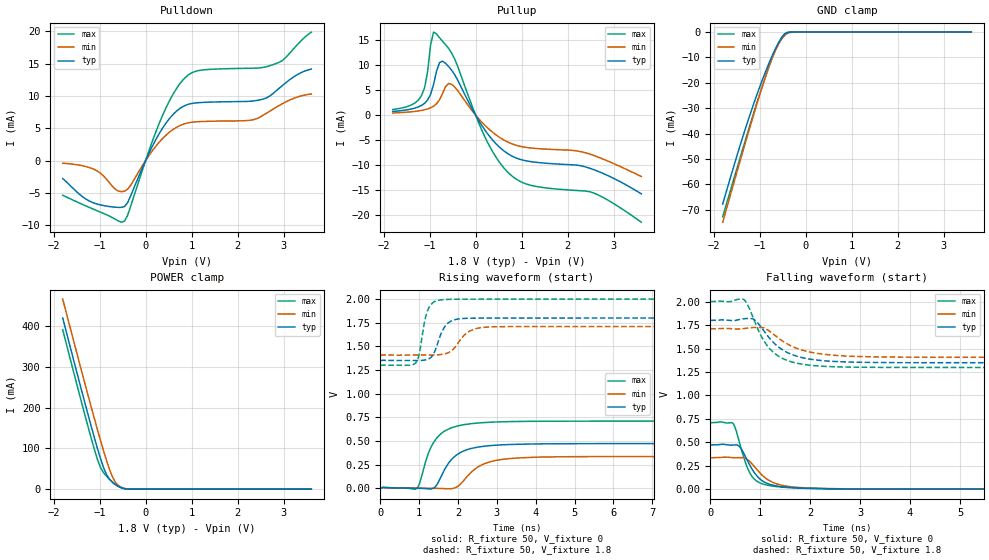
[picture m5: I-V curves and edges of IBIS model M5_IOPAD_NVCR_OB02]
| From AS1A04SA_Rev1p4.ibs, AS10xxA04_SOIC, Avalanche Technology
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[Model] M5_IOPAD_NVCR_OB02
Model_type I/O
Enable   Active-High
Vinl  =  0.54
Vinh  =  1.26
Vmeas =  0.9
Cref  =  30e-12
| Capacitance  typ   min   max
C_comp   3.869840e-12   3.575244e-12   4.229518e-12
| Variables   typ   min   max
[GND Clamp Reference]   0   0   0
[POWER Clamp Reference]   1.8   1.71   2
[Pulldown Reference]   0   0   0
[Pullup Reference]   1.8   1.71   2
[Temperature Range]   25   125   -40
[Voltage Range]   1.8   1.71   2
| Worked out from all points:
|   slope of the pulldown table from 0 to 0.27 V, typ, clamps not added: 70.1 ohm
|   slope of the pullup table from 0 to 0.27 V, typ, clamps not added: 70.5 ohm
|   GND clamp passes 1 mA (typ) near -0.46 V on its own axis
|   POWER clamp passes 1 mA (typ) near -0.44 V on its own axis
|   falling waveform, R_fixture 50, V_fixture 0: 20-80 % time 352ps typ, 436ps min, 280ps max; typ from 0.471 V to 0 V
|   falling waveform, R_fixture 50, V_fixture 1.8: 20-80 % time 579ps typ, 685ps min, 480ps max; typ from 1.8 V to 1.35 V
|   rising waveform, R_fixture 50, V_fixture 0: 20-80 % time 529ps typ, 625ps min, 463ps max; typ from 0 V to 0.471 V
|   rising waveform, R_fixture 50, V_fixture 1.8: 20-80 % time 269ps typ, 383ps min, 192ps max; typ from 1.35 V to 1.8 V
[GND Clamp]
| Voltage   I(typ)   I(min)   I(max)
-1.8V     -67.84mA   -74.98mA   -72.81mA
-1.499V   -49.26mA   -55.7mA    -54.28mA
-1.303V   -37.87mA   -43.36mA   -42.4mA
-1.043V   -23.96mA   -27.4mA    -27.1mA
-847.2mV  -14.58mA   -16.27mA   -16.36mA
-716.9mV  -8.973mA   -9.798mA   -9.837mA
-651.7mV  -6.447mA   -7.048mA   -6.896mA
-521.4mV  -2.255mA   -2.801mA   -2.141mA
-456.2mV  -849.3uA   -1.361mA   -679.4uA
-391mV    -172uA     -473.2uA   -88.88uA
-260.7mV  -2.088uA   -22.04uA   -254.3nA
3.6V      0A         0A         0A
[POWER Clamp]
| Voltage   I(typ)   I(min)   I(max)
-1.8V     419.8mA    466.1mA    390.9mA
-1.303V   205.4mA    252.8mA    175.7mA
-1.043V   98.85mA    144.9mA    72.14mA
-977.6mV  74.56mA    119mA      52.56mA
-912.4mV  52.76mA    93.87mA    40.16mA
-847.2mV  35.48mA    69.92mA    31.71mA
-716.9mV  16.42mA    29.44mA    17.31mA
-651.7mV  10.9mA     16.21mA    11.28mA
-586.6mV  6.514mA    8.5mA      6.386mA
-456.2mV  1.168mA    1.854mA    921.1uA
-325.9mV  31.2uA     159.5uA    13.68uA
3.6V      0A         0A         0A
[Pulldown]
| Voltage   I(typ)   I(min)   I(max)
-1.8V     -2.779mA   -403.4uA   -5.361mA
-1.173V   -6.412mA   -1.187mA   -7.394mA
-651.7mV  -7.214mA   -4.457mA   -9.099mA
-456.2mV  -7.098mA   -4.726mA   -9.361mA
310.3mV   4.353mA    2.972mA    6.008mA
620.7mV   7.316mA    4.933mA    10.57mA
869mV     8.567mA    5.75mA     12.9mA
1.179V    8.982mA    6.038mA    13.97mA
2.283V    9.19mA     6.258mA    14.3mA
2.766V    10.37mA    7.95mA     14.85mA
2.972V    11.63mA    8.812mA    15.49mA
3.6V      14.16mA    10.31mA    19.89mA
[Pullup]
| Voltage   I(typ)   I(min)   I(max)
-1.8V     713.6uA    418.6uA    1.098mA
-1.173V   1.921mA    929uA      3.898mA
-1.043V   2.99mA     1.225mA    8.588mA
-977.6mV  4.11mA     1.452mA    14mA
-912.4mV  6.104mA    1.777mA    16.54mA
-782.1mV  10.46mA    3.06mA     15.4mA
-651.7mV  10.31mA    5.686mA    14.04mA
-456.2mV  8.081mA    5.617mA    11.23mA
248.3mV   -3.569mA   -2.453mA   -5.217mA
744.8mV   -7.943mA   -5.559mA   -11.78mA
2.559V    -10.86mA   -8.024mA   -15.51mA
3.6V      -15.7mA    -12.25mA   -21.35mA
[Ramp]
dV/dt_r   0.282807/0.529465n  0.201049/0.625406n  0.425437/0.462933n
dV/dt_f   0.271206/0.579502n  0.182721/0.684992n  0.421848/0.479962n
R_load = 50
[Falling Waveform]
R_fixture = 50
V_fixture = 0
V_fixture_min = 0
V_fixture_max = 0
| Time   V(typ)   V(min)   V(max)
0s        471.3mV    335.1mV    709.1mV
456.1ps   470mV      334.8mV    699.6mV
507.4ps   472.5mV    335mV      640.9mV
592.1ps   450.1mV    336.1mV    482.5mV
743.8ps   304.7mV    315.6mV    226.6mV
918.2ps   151.1mV    218.6mV    90.72mV
1.152ns   58.72mV    100.6mV    41.21mV
1.537ns   20.7mV     31.46mV    17.55mV
3.312ns   1.001mV    1.561mV    678.5uV
21.88ns   148.3nV    1.007uV    196.1nV
[Falling Waveform]
R_fixture = 50
V_fixture = 1.8
V_fixture_min = 1.71
V_fixture_max = 2
| Time   V(typ)   V(min)   V(max)
0s        1.8V       1.71V      2V
668.7ps   1.817V     1.713V     2.023V
757.8ps   1.82V      1.719V     1.955V
896ps     1.802V     1.725V     1.779V
1.076ns   1.686V     1.719V     1.579V
1.279ns   1.556V     1.646V     1.452V
1.683ns   1.426V     1.512V     1.35V
2.237ns   1.371V     1.441V     1.311V
4.381ns   1.349V     1.406V     1.298V
21.88ns   1.348V     1.405V     1.297V
[Rising Waveform]
R_fixture = 50
V_fixture = 0
V_fixture_min = 0
V_fixture_max = 0
| Time   V(typ)   V(min)   V(max)
0s        64.51nV    875.2nV    117.5nV
929.7ps   137.8uV    994.8uV    -4.858mV
1.021ns   -1.205mV   800.6uV    63.07mV
1.241ns   -8.135mV   -80.01uV   372.4mV
1.458ns   37.82mV    -1.795mV   533.9mV
1.889ns   326.4mV    -47.96uV   645.9mV
2.545ns   436.5mV    231.5mV    690.7mV
3.129ns   458.2mV    304.1mV    702.2mV
4.501ns   469.7mV    331.2mV    708.3mV
21.88ns   471.3mV    335.1mV    709.1mV
[Rising Waveform]
R_fixture = 50
V_fixture = 1.8
V_fixture_min = 1.71
V_fixture_max = 2
| Time   V(typ)   V(min)   V(max)
0s        1.348V     1.405V     1.297V
908.2ps   1.349V     1.407V     1.323V
987.9ps   1.35V      1.407V     1.397V
1.13ns    1.354V     1.407V     1.742V
1.237ns   1.366V     1.407V     1.897V
1.37ns    1.419V     1.407V     1.966V
1.649ns   1.701V     1.42V      1.995V
2.265ns   1.797V     1.652V     1.999V
2.833ns   1.799V     1.705V     1.999V
21.88ns   1.8V       1.71V      2V
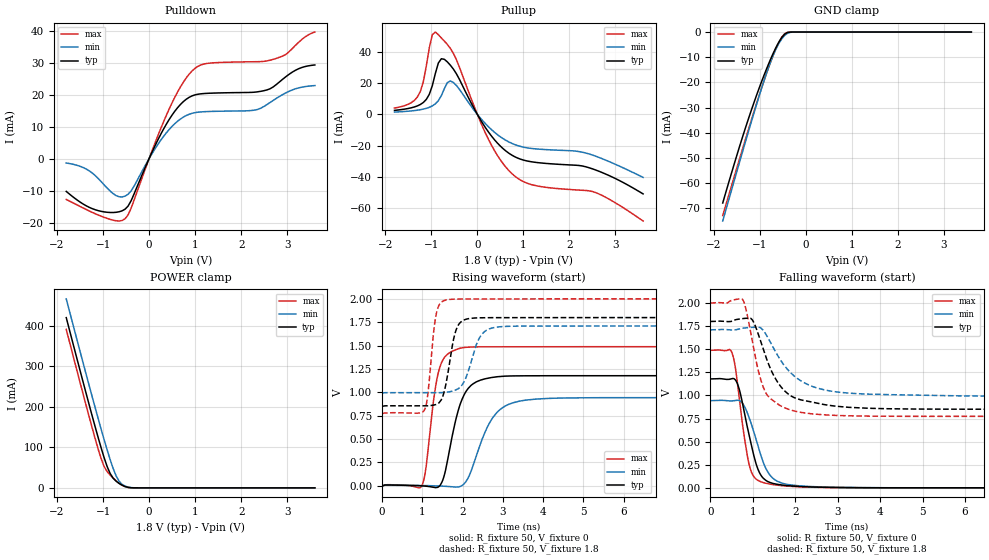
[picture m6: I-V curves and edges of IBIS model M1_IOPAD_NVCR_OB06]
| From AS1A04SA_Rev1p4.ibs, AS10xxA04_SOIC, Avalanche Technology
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[Model] M1_IOPAD_NVCR_OB06
Model_type I/O
Enable   Active-High
Vinl  =  0.54
Vinh  =  1.26
Vmeas =  0.9
Cref  =  30e-12
| Capacitance  typ   min   max
C_comp   3.869840e-12   3.575244e-12   4.229518e-12
| Variables   typ   min   max
[GND Clamp Reference]   0   0   0
[POWER Clamp Reference]   1.8   1.71   2
[Pulldown Reference]   0   0   0
[Pullup Reference]   1.8   1.71   2
[Temperature Range]   25   125   -40
[Voltage Range]   1.8   1.71   2
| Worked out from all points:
|   slope of the pulldown table from 0 to 0.27 V, typ, clamps not added: 33.5 ohm
|   slope of the pullup table from 0 to 0.27 V, typ, clamps not added: 21.7 ohm
|   GND clamp passes 1 mA (typ) near -0.46 V on its own axis
|   POWER clamp passes 1 mA (typ) near -0.44 V on its own axis
|   falling waveform, R_fixture 50, V_fixture 0: 20-80 % time 349ps typ, 414ps min, 269ps max; typ from 1.18 V to 0 V
|   falling waveform, R_fixture 50, V_fixture 1.8: 20-80 % time 603ps typ, 792ps min, 399ps max; typ from 1.8 V to 0.85 V
|   rising waveform, R_fixture 50, V_fixture 0: 20-80 % time 395ps typ, 556ps min, 266ps max; typ from 0 V to 1.18 V
|   rising waveform, R_fixture 50, V_fixture 1.8: 20-80 % time 237ps typ, 337ps min, 166ps max; typ from 0.85 V to 1.8 V
[GND Clamp]
| Voltage   I(typ)   I(min)   I(max)
-1.8V     -67.84mA   -74.98mA   -72.81mA
-1.499V   -49.26mA   -55.7mA    -54.28mA
-1.303V   -37.87mA   -43.36mA   -42.4mA
-1.043V   -23.96mA   -27.4mA    -27.1mA
-847.2mV  -14.58mA   -16.27mA   -16.36mA
-716.9mV  -8.973mA   -9.798mA   -9.837mA
-651.7mV  -6.447mA   -7.048mA   -6.896mA
-521.4mV  -2.255mA   -2.801mA   -2.141mA
-456.2mV  -849.3uA   -1.361mA   -679.4uA
-391mV    -172uA     -473.2uA   -88.88uA
-260.7mV  -2.088uA   -22.04uA   -254.3nA
3.6V      0A         0A         0A
[POWER Clamp]
| Voltage   I(typ)   I(min)   I(max)
-1.8V     419.8mA    466.1mA    390.9mA
-1.303V   205.4mA    252.8mA    175.7mA
-1.043V   98.85mA    144.9mA    72.14mA
-977.6mV  74.56mA    119mA      52.56mA
-912.4mV  52.76mA    93.87mA    40.16mA
-847.2mV  35.48mA    69.92mA    31.71mA
-716.9mV  16.42mA    29.44mA    17.31mA
-651.7mV  10.9mA     16.21mA    11.28mA
-586.6mV  6.514mA    8.5mA      6.386mA
-456.2mV  1.168mA    1.854mA    921.1uA
-325.9mV  31.2uA     159.5uA    13.68uA
3.6V      0A         0A         0A
[Pulldown]
| Voltage   I(typ)   I(min)   I(max)
-1.8V     -10.27mA   -1.377mA   -12.78mA
-1.108V   -16.27mA   -6.192mA   -17.63mA
-716.9mV  -16.8mA    -11.58mA   -19.45mA
-521.4mV  -15.81mA   -11.74mA   -18.8mA
-391mV    -13.18mA   -10.1mA    -15.51mA
372.4mV   10.72mA    8.023mA    13.47mA
931mV     19.6mA     14.15mA    27.38mA
1.241V    20.39mA    14.69mA    29.72mA
2.283V    20.76mA    15.14mA    30.29mA
2.697V    22.43mA    18.2mA     31.03mA
3.179V    27.62mA    21.83mA    35.42mA
3.6V      29.28mA    22.83mA    39.58mA
[Pullup]
| Voltage   I(typ)   I(min)   I(max)
-1.8V     2.579mA    1.494mA    4.066mA
-1.238V   6.367mA    3.011mA    14.71mA
-977.6mV  18.53mA    5.465mA    51.24mA
-912.4mV  26.3mA     6.791mA    52.93mA
-782.1mV  35.76mA    12.04mA    49.13mA
-651.7mV  33.73mA    20.39mA    44.94mA
-521.4mV  29.14mA    20.54mA    39.28mA
186.2mV   -8.975mA   -6.295mA   -12.69mA
744.8mV   -26.1mA    -18.58mA   -37.9mA
1.241V    -30.74mA   -22.09mA   -45.62mA
2.559V    -35.62mA   -26.73mA   -50.14mA
3.6V      -51.1mA    -40.49mA   -68.52mA
[Ramp]
dV/dt_r   0.70702/0.39465n  0.566097/0.556387n  0.892904/0.26596n
dV/dt_f   0.569737/0.602924n  0.430715/0.791806n  0.736237/0.398943n
R_load = 50
[Falling Waveform]
R_fixture = 50
V_fixture = 0
V_fixture_min = 0
V_fixture_max = 0
| Time   V(typ)   V(min)   V(max)
0s        1.178V     943.5mV    1.488V
505.1ps   1.181V     940.6mV    1.468V
580.5ps   1.173V     945.6mV    1.331V
666.6ps   1.092V     947.3mV    1.026V
802.5ps   815.2mV    883.3mV    548.2mV
942.9ps   513.8mV    723.4mV    204.1mV
1.169ns   155.3mV    384.4mV    69.9mV
1.455ns   50.58mV    112.7mV    36.41mV
3.27ns    2.368mV    3.858mV    1.53mV
21.88ns   366.3nV    1.238uV    391.8nV
[Falling Waveform]
R_fixture = 50
V_fixture = 1.8
V_fixture_min = 1.71
V_fixture_max = 2
| Time   V(typ)   V(min)   V(max)
0s        1.8V       1.71V      2V
755.5ps   1.831V     1.727V     2.041V
844.1ps   1.835V     1.732V     1.927V
996.5ps   1.813V     1.737V     1.569V
1.16ns    1.624V     1.737V     1.217V
1.324ns   1.398V     1.652V     1.016V
1.745ns   1.052V     1.324V     867.5mV
2.335ns   934mV      1.11V      803.4mV
5.615ns   851.2mV    996mV      773.6mV
21.88ns   850.4mV    992.1mV    772.9mV
[Rising Waveform]
R_fixture = 50
V_fixture = 0
V_fixture_min = 0
V_fixture_max = 0
| Time   V(typ)   V(min)   V(max)
0s        82.33nV    858.7nV    142.2nV
973ps     173.1uV    2.939mV    -10.32mV
1.088ns   -3.879mV   2.255mV    184mV
1.28ns    -16.31mV   191.4uV    915.4mV
1.431ns   279.3uV    -2.2mV     1.264V
1.99ns    928.5mV    3.83mV     1.477V
2.258ns   1.09V      213.3mV    1.486V
2.757ns   1.161V     733.4mV    1.487V
3.563ns   1.177V     916.5mV    1.488V
21.88ns   1.178V     943.5mV    1.488V
[Rising Waveform]
R_fixture = 50
V_fixture = 1.8
V_fixture_min = 1.71
V_fixture_max = 2
| Time   V(typ)   V(min)   V(max)
0s        850.4mV    992.1mV    772.9mV
1.064ns   854.1mV    995.5mV    819mV
1.134ns   855.2mV    995.3mV    971.4mV
1.336ns   869.6mV    995.1mV    1.817V
1.512ns   961.3mV    997.5mV    1.976V
1.639ns   1.214V     1.004V     1.992V
1.926ns   1.739V     1.051V     1.998V
2.46ns    1.798V     1.61V      1.999V
2.996ns   1.799V     1.704V     1.999V
21.88ns   1.8V       1.71V      2V
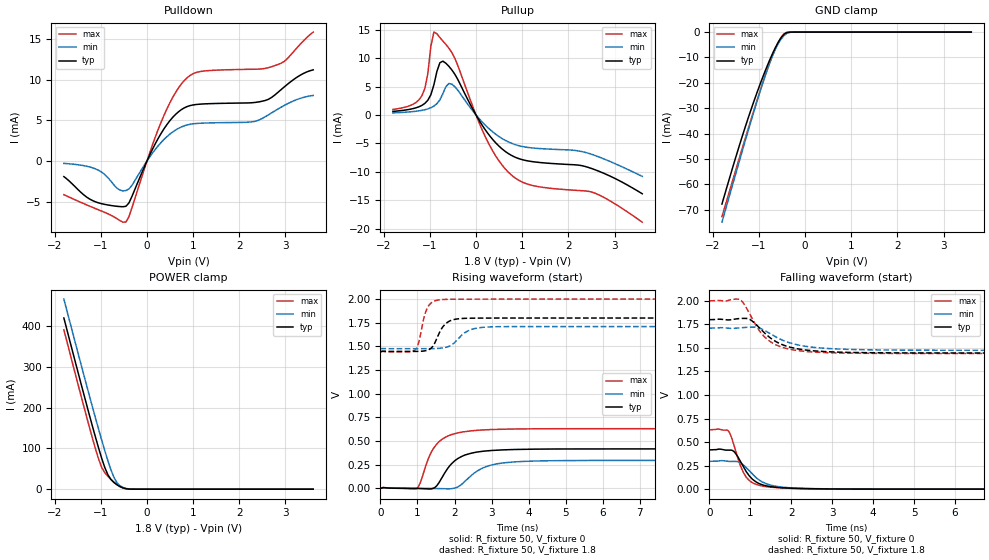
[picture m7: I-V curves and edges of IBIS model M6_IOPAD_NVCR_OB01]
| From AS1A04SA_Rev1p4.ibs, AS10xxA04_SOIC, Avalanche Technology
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[Model] M6_IOPAD_NVCR_OB01
Model_type I/O
Enable   Active-High
Vinl  =  0.54
Vinh  =  1.26
Vmeas =  0.9
Cref  =  30e-12
| Capacitance  typ   min   max
C_comp   3.869840e-12   3.575244e-12   4.229518e-12
| Variables   typ   min   max
[GND Clamp Reference]   0   0   0
[POWER Clamp Reference]   1.8   1.71   2
[Pulldown Reference]   0   0   0
[Pullup Reference]   1.8   1.71   2
[Temperature Range]   25   125   -40
[Voltage Range]   1.8   1.71   2
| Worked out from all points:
|   slope of the pulldown table from 0 to 0.27 V, typ, clamps not added: 88.4 ohm
|   slope of the pullup table from 0 to 0.27 V, typ, clamps not added: 80.1 ohm
|   GND clamp passes 1 mA (typ) near -0.46 V on its own axis
|   POWER clamp passes 1 mA (typ) near -0.44 V on its own axis
|   falling waveform, R_fixture 50, V_fixture 0: 20-80 % time 409ps typ, 500ps min, 329ps max; typ from 0.417 V to 0 V
|   falling waveform, R_fixture 50, V_fixture 1.8: 20-80 % time 714ps typ, 848ps min, 588ps max; typ from 1.8 V to 1.45 V
|   rising waveform, R_fixture 50, V_fixture 0: 20-80 % time 559ps typ, 669ps min, 484ps max; typ from 0 V to 0.417 V
|   rising waveform, R_fixture 50, V_fixture 1.8: 20-80 % time 291ps typ, 416ps min, 205ps max; typ from 1.45 V to 1.8 V
[GND Clamp]
| Voltage   I(typ)   I(min)   I(max)
-1.8V     -67.84mA   -74.98mA   -72.81mA
-1.499V   -49.26mA   -55.7mA    -54.28mA
-1.303V   -37.87mA   -43.36mA   -42.4mA
-1.043V   -23.96mA   -27.4mA    -27.1mA
-847.2mV  -14.58mA   -16.27mA   -16.36mA
-716.9mV  -8.973mA   -9.798mA   -9.837mA
-651.7mV  -6.447mA   -7.048mA   -6.896mA
-521.4mV  -2.255mA   -2.801mA   -2.141mA
-456.2mV  -849.3uA   -1.361mA   -679.4uA
-391mV    -172uA     -473.2uA   -88.88uA
-260.7mV  -2.088uA   -22.04uA   -254.3nA
3.6V      0A         0A         0A
[POWER Clamp]
| Voltage   I(typ)   I(min)   I(max)
-1.8V     419.8mA    466.1mA    390.9mA
-1.303V   205.4mA    252.8mA    175.7mA
-1.043V   98.85mA    144.9mA    72.14mA
-977.6mV  74.56mA    119mA      52.56mA
-912.4mV  52.76mA    93.87mA    40.16mA
-847.2mV  35.48mA    69.92mA    31.71mA
-716.9mV  16.42mA    29.44mA    17.31mA
-651.7mV  10.9mA     16.21mA    11.28mA
-586.6mV  6.514mA    8.5mA      6.386mA
-456.2mV  1.168mA    1.854mA    921.1uA
-325.9mV  31.2uA     159.5uA    13.68uA
3.6V      0A         0A         0A
[Pulldown]
| Voltage   I(typ)   I(min)   I(max)
-1.8V     -1.924mA   -299.7uA   -4.159mA
-1.173V   -4.896mA   -848.4uA   -5.734mA
-912.4mV  -5.354mA   -1.678mA   -6.345mA
-651.7mV  -5.587mA   -3.335mA   -7.105mA
-456.2mV  -5.586mA   -3.649mA   -7.526mA
310.3mV   3.446mA    2.313mA    4.855mA
558.6mV   5.391mA    3.587mA    7.858mA
806.9mV   6.547mA    4.337mA    9.919mA
1.179V    7.023mA    4.664mA    11.06mA
2.283V    7.188mA    4.836mA    11.32mA
2.834V    8.456mA    6.4mA      11.9mA
3.6V      11.24mA    8.086mA    15.9mA
[Pullup]
| Voltage   I(typ)   I(min)   I(max)
-1.8V     628.3uA    368.4uA    967.2uA
-1.173V   1.677mA    813.9uA    3.367mA
-1.043V   2.6mA      1.072mA    7.324mA
-977.6mV  3.564mA    1.27mA     12.11mA
-912.4mV  5.287mA    1.553mA    14.55mA
-782.1mV  9.175mA    2.668mA    13.58mA
-651.7mV  9.08mA     4.977mA    12.38mA
-456.2mV  7.117mA    4.941mA    9.904mA
248.3mV   -3.143mA   -2.157mA   -4.604mA
744.8mV   -6.991mA   -4.887mA   -10.39mA
2.559V    -9.556mA   -7.056mA   -13.67mA
3.6V      -13.83mA   -10.77mA   -18.82mA
[Ramp]
dV/dt_r   0.25025/0.55882n  0.177383/0.668972n  0.378271/0.483969n
dV/dt_f   0.212589/0.713715n  0.1414/0.848322n  0.335614/0.588184n
R_load = 50
[Falling Waveform]
R_fixture = 50
V_fixture = 0
V_fixture_min = 0
V_fixture_max = 0
| Time   V(typ)   V(min)   V(max)
0s        417.1mV    295.6mV    630.5mV
463.6ps   414.7mV    294.6mV    617.4mV
530.2ps   414.8mV    294.3mV    558.9mV
607ps     395.5mV    295mV      453.7mV
789.6ps   268.3mV    270.1mV    214.1mV
994.9ps   130.2mV    184.5mV    84.28mV
1.299ns   45.24mV    74.67mV    33.1mV
1.728ns   16.33mV    24.14mV    13.57mV
3.572ns   849.7uV    1.332mV    584.9uV
21.88ns   104.5nV    948.1nV    135.6nV
[Falling Waveform]
R_fixture = 50
V_fixture = 1.8
V_fixture_min = 1.71
V_fixture_max = 2
| Time   V(typ)   V(min)   V(max)
0s        1.8V       1.71V      2V
734.6ps   1.812V     1.714V     2.017V
834.5ps   1.814V     1.717V     1.973V
990.2ps   1.802V     1.72V      1.855V
1.229ns   1.71V      1.71V      1.676V
1.448ns   1.619V     1.66V      1.578V
1.883ns   1.519V     1.565V     1.493V
2.543ns   1.469V     1.506V     1.456V
4.958ns   1.447V     1.476V     1.441V
21.88ns   1.446V     1.474V     1.441V
[Rising Waveform]
R_fixture = 50
V_fixture = 0
V_fixture_min = 0
V_fixture_max = 0
| Time   V(typ)   V(min)   V(max)
0s        58.89nV    879.9nV    108.9nV
967.4ps   -441.9uV   -197.4uV   -3.638mV
1.074ns   -1.686mV   -256.9uV   57.27mV
1.349ns   -6.571mV   -673.1uV   362.9mV
1.583ns   61.13mV    -2.269mV   493.5mV
2.013ns   293.6mV    3.425mV    578.7mV
2.666ns   386.6mV    195.6mV    614.9mV
3.301ns   406.4mV    268.4mV    625.1mV
4.723ns   415.8mV    292.5mV    629.9mV
21.88ns   417.1mV    295.6mV    630.5mV
[Rising Waveform]
R_fixture = 50
V_fixture = 1.8
V_fixture_min = 1.71
V_fixture_max = 2
| Time   V(typ)   V(min)   V(max)
0s        1.446V     1.474V     1.441V
944.3ps   1.447V     1.475V     1.466V
1.021ns   1.447V     1.475V     1.524V
1.268ns   1.459V     1.475V     1.907V
1.438ns   1.514V     1.476V     1.976V
1.644ns   1.683V     1.482V     1.994V
2.009ns   1.786V     1.543V     1.999V
2.402ns   1.798V     1.671V     1.999V
3.022ns   1.799V     1.707V     1.999V
21.88ns   1.8V       1.71V      2V
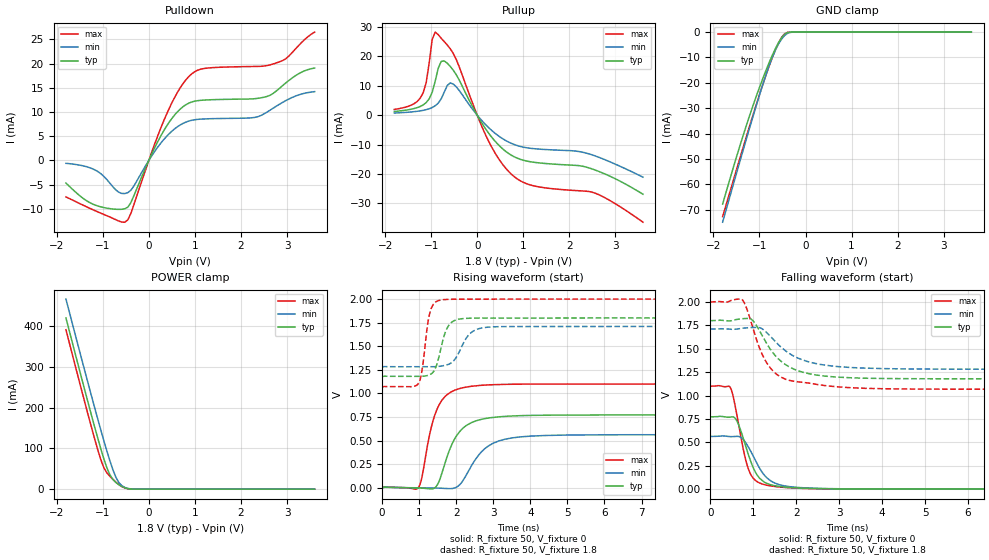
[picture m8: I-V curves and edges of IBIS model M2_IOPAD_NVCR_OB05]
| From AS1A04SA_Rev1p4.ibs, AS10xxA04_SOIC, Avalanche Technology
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[Model] M2_IOPAD_NVCR_OB05
Model_type I/O
Enable   Active-High
Vinl  =  0.54
Vinh  =  1.26
Vmeas =  0.9
Cref  =  30e-12
| Capacitance  typ   min   max
C_comp   3.869840e-12   3.575244e-12   4.229518e-12
| Variables   typ   min   max
[GND Clamp Reference]   0   0   0
[POWER Clamp Reference]   1.8   1.71   2
[Pulldown Reference]   0   0   0
[Pullup Reference]   1.8   1.71   2
[Temperature Range]   25   125   -40
[Voltage Range]   1.8   1.71   2
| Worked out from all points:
|   slope of the pulldown table from 0 to 0.27 V, typ, clamps not added: 51.8 ohm
|   slope of the pullup table from 0 to 0.27 V, typ, clamps not added: 41.1 ohm
|   GND clamp passes 1 mA (typ) near -0.46 V on its own axis
|   POWER clamp passes 1 mA (typ) near -0.44 V on its own axis
|   falling waveform, R_fixture 50, V_fixture 0: 20-80 % time 370ps typ, 451ps min, 301ps max; typ from 0.772 V to 0 V
|   falling waveform, R_fixture 50, V_fixture 1.8: 20-80 % time 687ps typ, 823ps min, 547ps max; typ from 1.8 V to 1.18 V
|   rising waveform, R_fixture 50, V_fixture 0: 20-80 % time 530ps typ, 658ps min, 413ps max; typ from 0 V to 0.772 V
|   rising waveform, R_fixture 50, V_fixture 1.8: 20-80 % time 261ps typ, 373ps min, 184ps max; typ from 1.18 V to 1.8 V
[GND Clamp]
| Voltage   I(typ)   I(min)   I(max)
-1.8V     -67.84mA   -74.98mA   -72.81mA
-1.499V   -49.26mA   -55.7mA    -54.28mA
-1.303V   -37.87mA   -43.36mA   -42.4mA
-1.043V   -23.96mA   -27.4mA    -27.1mA
-847.2mV  -14.58mA   -16.27mA   -16.36mA
-716.9mV  -8.973mA   -9.798mA   -9.837mA
-651.7mV  -6.447mA   -7.048mA   -6.896mA
-521.4mV  -2.255mA   -2.801mA   -2.141mA
-456.2mV  -849.3uA   -1.361mA   -679.4uA
-391mV    -172uA     -473.2uA   -88.88uA
-260.7mV  -2.088uA   -22.04uA   -254.3nA
3.6V      0A         0A         0A
[POWER Clamp]
| Voltage   I(typ)   I(min)   I(max)
-1.8V     419.8mA    466.1mA    390.9mA
-1.303V   205.4mA    252.8mA    175.7mA
-1.043V   98.85mA    144.9mA    72.14mA
-977.6mV  74.56mA    119mA      52.56mA
-912.4mV  52.76mA    93.87mA    40.16mA
-847.2mV  35.48mA    69.92mA    31.71mA
-716.9mV  16.42mA    29.44mA    17.31mA
-651.7mV  10.9mA     16.21mA    11.28mA
-586.6mV  6.514mA    8.5mA      6.386mA
-456.2mV  1.168mA    1.854mA    921.1uA
-325.9mV  31.2uA     159.5uA    13.68uA
3.6V      0A         0A         0A
[Pulldown]
| Voltage   I(typ)   I(min)   I(max)
-1.8V     -4.699mA   -619.1uA   -7.55mA
-1.238V   -8.945mA   -1.682mA   -10.1mA
-521.4mV  -10.01mA   -6.861mA   -12.78mA
-391mV    -8.736mA   -6.178mA   -10.98mA
62.07mV   1.302mA    930.2uA    1.683mA
372.4mV   6.876mA    4.82mA     9.257mA
869mV     11.82mA    8.118mA    17.32mA
1.179V    12.44mA    8.54mA     18.94mA
2.283V    12.72mA    8.843mA    19.39mA
2.766V    14.31mA    11.17mA    20.12mA
3.248V    17.87mA    13.5mA     23.67mA
3.6V      19.07mA    14.19mA    26.49mA
[Pullup]
| Voltage   I(typ)   I(min)   I(max)
-1.8V     1.265mA    738.8uA    1.963mA
-1.173V   3.489mA    1.648mA    7.625mA
-1.108V   4.286mA    1.879mA    11.06mA
-977.6mV  7.759mA    2.597mA    25.76mA
-912.4mV  11.52mA    3.193mA    28.29mA
-782.1mV  18.3mA     5.553mA    26.2mA
-521.4mV  15.35mA    10.63mA    21.07mA
186.2mV   -4.735mA   -3.27mA    -6.841mA
744.8mV   -13.65mA   -9.606mA   -20.12mA
1.241V    -16.05mA   -11.42mA   -24.1mA
2.559V    -18.65mA   -13.85mA   -26.53mA
3.6V      -26.91mA   -21.09mA   -36.43mA
[Ramp]
dV/dt_r   0.463316/0.530243n  0.337691/0.657568n  0.66012/0.41274n
dV/dt_f   0.372865/0.686555n  0.257384/0.822818n  0.559402/0.546995n
R_load = 50
[Falling Waveform]
R_fixture = 50
V_fixture = 0
V_fixture_min = 0
V_fixture_max = 0
| Time   V(typ)   V(min)   V(max)
0s        772.2mV    562.8mV    1.1V
480.1ps   771mV      560.9mV    1.075V
545.6ps   770.1mV    561.6mV    969.9mV
639ps     712.4mV    564.7mV    745.7mV
823ps     464.3mV    498.9mV    318mV
970.5ps   264mV      381.1mV    136.6mV
1.21ns    91.22mV    179.4mV    55.35mV
1.59ns    29.99mV    50.83mV    23.79mV
3.456ns   1.358mV    2.175mV    883.1uV
21.88ns   194.5nV    1.022uV    178.6nV
[Falling Waveform]
R_fixture = 50
V_fixture = 1.8
V_fixture_min = 1.71
V_fixture_max = 2
| Time   V(typ)   V(min)   V(max)
0s        1.8V       1.71V      2V
748.5ps   1.821V     1.719V     2.023V
854.9ps   1.824V     1.724V     1.923V
976ps     1.808V     1.727V     1.748V
1.206ns   1.645V     1.714V     1.444V
1.547ns   1.41V      1.562V     1.227V
2.115ns   1.255V     1.386V     1.143V
2.869ns   1.2V       1.314V     1.097V
5.496ns   1.179V     1.282V     1.068V
21.88ns   1.179V     1.281V     1.068V
[Rising Waveform]
R_fixture = 50
V_fixture = 0
V_fixture_min = 0
V_fixture_max = 0
| Time   V(typ)   V(min)   V(max)
0s        71.62nV    860.1nV    128.3nV
964.7ps   -357uV     915.8uV    -7.097mV
1.081ns   -2.826mV   765.9uV    113.4mV
1.359ns   -11.16mV   -999.5uV   683.5mV
1.543ns   70.17mV    -3.215mV   879.7mV
1.949ns   510.1mV    -2.221mV   1.032V
2.404ns   688.6mV    226.5mV    1.076V
3.011ns   746.7mV    474.7mV    1.093V
4.311ns   769.2mV    553.4mV    1.1V
21.88ns   772.2mV    562.8mV    1.1V
[Rising Waveform]
R_fixture = 50
V_fixture = 1.8
V_fixture_min = 1.71
V_fixture_max = 2
| Time   V(typ)   V(min)   V(max)
0s        1.178V     1.281V     1.068V
972.5ps   1.18V      1.282V     1.098V
1.075ns   1.181V     1.282V     1.227V
1.3ns     1.2V       1.282V     1.863V
1.465ns   1.287V     1.284V     1.972V
1.636ns   1.551V     1.292V     1.993V
1.977ns   1.776V     1.366V     1.998V
2.373ns   1.797V     1.633V     1.999V
2.935ns   1.799V     1.704V     2V
21.88ns   1.8V       1.71V      2V
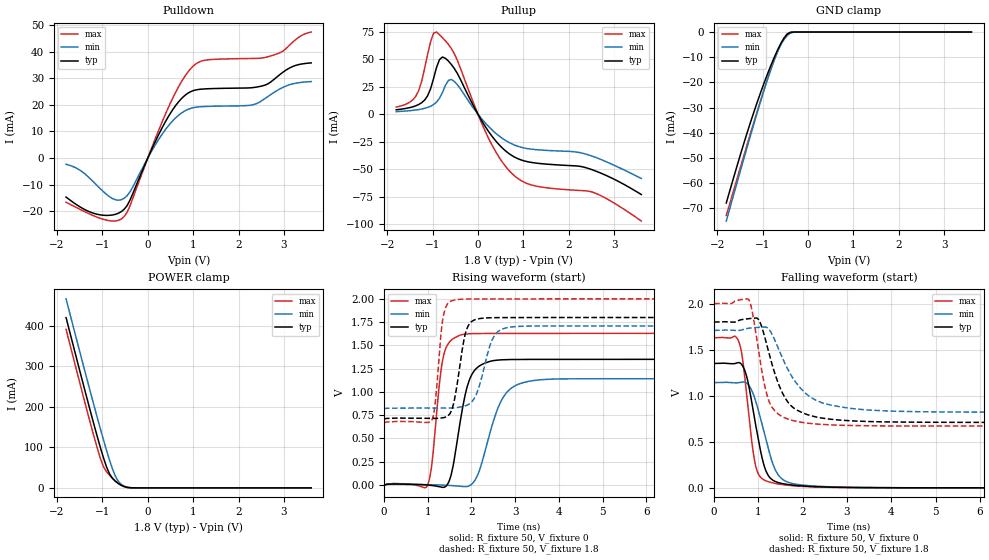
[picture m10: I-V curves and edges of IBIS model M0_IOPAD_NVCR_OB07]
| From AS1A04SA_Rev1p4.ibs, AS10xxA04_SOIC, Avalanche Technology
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[Model] M0_IOPAD_NVCR_OB07
Model_type I/O
Enable   Active-High
Vinl  =  0.54
Vinh  =  1.26
Vmeas =  0.9
Cref  =  30e-12
| Capacitance  typ   min   max
C_comp   3.869840e-12   3.575244e-12   4.229518e-12
| Variables   typ   min   max
[GND Clamp Reference]   0   0   0
[POWER Clamp Reference]   1.8   1.71   2
[Pulldown Reference]   0   0   0
[Pullup Reference]   1.8   1.71   2
[Temperature Range]   25   125   -40
[Voltage Range]   1.8   1.71   2
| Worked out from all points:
|   slope of the pulldown table from 0 to 0.27 V, typ, clamps not added: 27.4 ohm
|   slope of the pullup table from 0 to 0.27 V, typ, clamps not added: 15.2 ohm
|   GND clamp passes 1 mA (typ) near -0.46 V on its own axis
|   POWER clamp passes 1 mA (typ) near -0.44 V on its own axis
|   falling waveform, R_fixture 50, V_fixture 0: 20-80 % time 318ps typ, 395ps min, 234ps max; typ from 1.35 V to 0 V
|   falling waveform, R_fixture 50, V_fixture 1.8: 20-80 % time 494ps typ, 703ps min, 317ps max; typ from 1.8 V to 0.711 V
|   rising waveform, R_fixture 50, V_fixture 0: 20-80 % time 313ps typ, 460ps min, 208ps max; typ from 0 V to 1.35 V
|   rising waveform, R_fixture 50, V_fixture 1.8: 20-80 % time 222ps typ, 318ps min, 147ps max; typ from 0.711 V to 1.8 V
[GND Clamp]
| Voltage   I(typ)   I(min)   I(max)
-1.8V     -67.84mA   -74.98mA   -72.81mA
-1.499V   -49.26mA   -55.7mA    -54.28mA
-1.303V   -37.87mA   -43.36mA   -42.4mA
-1.043V   -23.96mA   -27.4mA    -27.1mA
-847.2mV  -14.58mA   -16.27mA   -16.36mA
-716.9mV  -8.973mA   -9.798mA   -9.837mA
-651.7mV  -6.447mA   -7.048mA   -6.896mA
-521.4mV  -2.255mA   -2.801mA   -2.141mA
-456.2mV  -849.3uA   -1.361mA   -679.4uA
-391mV    -172uA     -473.2uA   -88.88uA
-260.7mV  -2.088uA   -22.04uA   -254.3nA
3.6V      0A         0A         0A
[POWER Clamp]
| Voltage   I(typ)   I(min)   I(max)
-1.8V     419.8mA    466.1mA    390.9mA
-1.303V   205.4mA    252.8mA    175.7mA
-1.043V   98.85mA    144.9mA    72.14mA
-977.6mV  74.56mA    119mA      52.56mA
-912.4mV  52.76mA    93.87mA    40.16mA
-847.2mV  35.48mA    69.92mA    31.71mA
-716.9mV  16.42mA    29.44mA    17.31mA
-651.7mV  10.9mA     16.21mA    11.28mA
-586.6mV  6.514mA    8.5mA      6.386mA
-456.2mV  1.168mA    1.854mA    921.1uA
-325.9mV  31.2uA     159.5uA    13.68uA
3.6V      0A         0A         0A
[Pulldown]
| Voltage   I(typ)   I(min)   I(max)
-1.8V     -14.7mA    -2.359mA   -16.67mA
-1.173V   -20.9mA    -9.386mA   -21.89mA
-586.6mV  -20.2mA    -15.7mA    -22.98mA
-391mV    -15.81mA   -12.74mA   -17.94mA
434.5mV   15.06mA    11.71mA    18.3mA
744.8mV   22.41mA    16.97mA    28.81mA
993.1mV   25.32mA    18.91mA    34.48mA
1.303V    26.05mA    19.41mA    36.91mA
2.283V    26.44mA    19.93mA    37.46mA
2.697V    28.46mA    23.74mA    38.33mA
3.179V    34.35mA    27.86mA    43.4mA
3.6V      35.79mA    28.77mA    47.41mA
[Pullup]
| Voltage   I(typ)   I(min)   I(max)
-1.8V     3.929mA    2.254mA    6.328mA
-1.369V   7.544mA    3.734mA    16.15mA
-1.108V   16.63mA    6.042mA    54.24mA
-977.6mV  32.17mA    8.632mA    73.42mA
-912.4mV  42.21mA    10.85mA    74.52mA
-782.1mV  51.81mA    19.47mA    69.4mA
-586.6mV  45.15mA    31.4mA     59.67mA
248.3mV   -16.56mA   -11.79mA   -23.05mA
744.8mV   -37.5mA    -26.97mA   -53.73mA
1.241V    -44.25mA   -32.11mA   -64.98mA
2.559V    -51.13mA   -38.74mA   -71.32mA
3.6V      -73.01mA   -58.39mA   -97.05mA
[Ramp]
dV/dt_r   0.810285/0.312866n  0.68564/0.460416n  0.977638/0.208143n
dV/dt_f   0.653673/0.494413n  0.533416/0.703261n  0.797534/0.316527n
R_load = 50
[Falling Waveform]
R_fixture = 50
V_fixture = 0
V_fixture_min = 0
V_fixture_max = 0
| Time   V(typ)   V(min)   V(max)
0s        1.35V      1.143V     1.629V
542ps     1.36V      1.141V     1.606V
629.8ps   1.336V     1.149V     1.446V
734.7ps   1.213V     1.138V     1.022V
866.2ps   887.8mV    1.042V     448.9mV
949.7ps   657.2mV    927.5mV    218.5mV
1.175ns   179.9mV    524.4mV    75.52mV
1.514ns   49.17mV    105.9mV    37mV
3.331ns   2.775mV    4.374mV    1.756mV
21.88ns   541.3nV    1.475uV    488.8nV
[Falling Waveform]
R_fixture = 50
V_fixture = 1.8
V_fixture_min = 1.71
V_fixture_max = 2
| Time   V(typ)   V(min)   V(max)
0s        1.8V       1.71V      2V
777.8ps   1.837V     1.733V     2.047V
868.5ps   1.841V     1.737V     1.899V
1.028ns   1.808V     1.743V     1.417V
1.269ns   1.412V     1.702V     909mV
1.651ns   940.8mV    1.302V     749.7mV
2.09ns    797.8mV    1.018V     703.5mV
2.896ns   733.6mV    876.2mV    679mV
4.51ns    712.9mV    827.3mV    671.5mV
21.88ns   710.5mV    821mV      670.8mV
[Rising Waveform]
R_fixture = 50
V_fixture = 0
V_fixture_min = 0
V_fixture_max = 0
| Time   V(typ)   V(min)   V(max)
0s        87.47nV    874.1nV    147.8nV
983.1ps   758.9uV    4.625mV    -13.23mV
1.089ns   -4.069mV   3.848mV    198.8mV
1.357ns   -25.09mV   -511.1uV   1.378V
1.535ns   106.6mV    -5.002mV   1.555V
1.829ns   908mV      -16.93mV   1.62V
2.112ns   1.253V     77.68mV    1.628V
2.742ns   1.346V     953.9mV    1.629V
3.454ns   1.35V      1.125V     1.629V
21.88ns   1.35V      1.143V     1.629V
[Rising Waveform]
R_fixture = 50
V_fixture = 1.8
V_fixture_min = 1.71
V_fixture_max = 2
| Time   V(typ)   V(min)   V(max)
0s        710.5mV    821mV      670.8mV
1.098ns   715.4mV    826.3mV    701.2mV
1.175ns   715.6mV    826mV      895.6mV
1.359ns   723.6mV    826.2mV    1.818V
1.644ns   999.8mV    830.8mV    1.991V
1.828ns   1.56V      846.4mV    1.997V
1.964ns   1.738V     876.1mV    1.999V
2.502ns   1.798V     1.586V     1.999V
2.967ns   1.799V     1.701V     2V
21.88ns   1.8V       1.71V      2V
